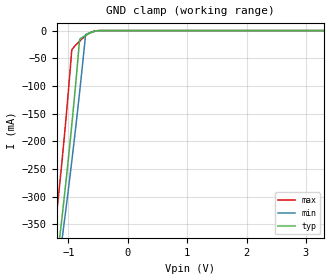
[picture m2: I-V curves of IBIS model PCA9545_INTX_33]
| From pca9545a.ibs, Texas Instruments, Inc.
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[Model]   PCA9545_INTX_33
Model_type  Input
Vinl=0.9
Vinh=2.52
| variable   typ   min   max
C_comp   2.06pF   1.51pF   4.70pF
[Temperature Range]   40   100   -40
| Ambient temperature   25   85   -40
[Voltage range]   3.3   3   3.6
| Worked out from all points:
|   GND clamp passes 1 mA (typ) near -0.54 V on its own axis
[GND Clamp]
| PCA9545_INTX_33
|   Voltage   I(typ)   I(min)   I(max)
-5.5V     -1.952A    -1.991A    -1.822A
-1.24V    -456.1mA   -482.2mA   -371.1mA
-1.205V   -425.8mA   -455.2mA   -337.1mA
-1.135V   -362.9mA   -399.8mA   -265.2mA
-1.1V     -330.1mA   -371.2mA   -227.1mA
-1.07V    -301.2mA   -346.3mA   -193.2mA
-1.005V   -236.2mA   -290.9mA   -115.2mA
-945mV    -172.6mA   -237.7mA   -36.94mA
-810mV    -16.02mA   -110.1mA   -19.15mA
-710mV    -8.623mA   -7.36mA    -9.218mA
-505mV    -240uA     -374.5uA   -17.49uA
3.3V      82.96pA    248pA      52.06pA
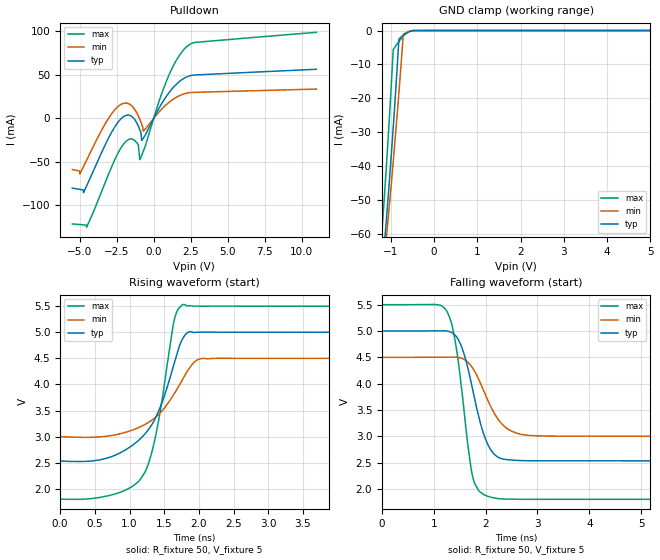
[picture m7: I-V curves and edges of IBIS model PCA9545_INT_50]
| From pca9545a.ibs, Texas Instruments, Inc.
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[Model]   PCA9545_INT_50
Model_type  Open_drain
Enable   Active-Low
Vref =   5V
Rref =   1k
Cref =   50p
Vmeas =   2.5
| variable   typ   min   max
C_comp   0.16pF   0.14pF   0.20pF
| C_pulldown   0.50pF   0.33pF   0.70pF
| C_tri-state   0.16pF   0.14pF   0.20pF
[Temperature Range]   40   100   -40
| Ambient temperature   25   85   -40
[Voltage range]   5   4.5   5.5
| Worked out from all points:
|   slope of the pulldown table from 0 to 0.75 V, typ, clamps not added: 33.3 ohm
|   GND clamp passes 1 mA (typ) near -0.66 V on its own axis
|   rising waveform, R_fixture 50, V_fixture 5: 20-80 % time 462ps typ, 504ps min, 300ps max; typ from 2.53 V to 5 V
|   falling waveform, R_fixture 50, V_fixture 5: 20-80 % time 368ps typ, 451ps min, 277ps max; typ from 5 V to 2.53 V
[GND Clamp]
| PCA9545_INT_50
|   Voltage   I(typ)   I(min)   I(max)
-5.5V     -353mA     -340.2mA   -363.4mA
-1.2V     -71.19mA   -74.19mA   -58.77mA
-1.125V   -59.7mA    -64.38mA   -44.86mA
-1.105V   -56.52mA   -61.69mA   -40.97mA
-1.09V    -54.11mA   -59.66mA   -37.99mA
-1.07V    -50.85mA   -56.93mA   -33.93mA
-940mV    -28.2mA    -38.37mA   -5.645mA
-810mV    -2.594mA   -18.16mA   -3.228mA
-710mV    -1.419mA   -1.185mA   -1.625mA
-620mV    -644.8uA   -525uA     -621.6uA
-480mV    -17.76uA   -26.37uA   -2.003uA
5V        25.68pA    51.58pA    20.07pA
[Pulldown]
| PCA9545_INT_50
|   Voltage   I(typ)   I(min)   I(max)
-5.5V     -80.34mA   -58.86mA   -121.5mA
-4.995V   -81.71mA   -64.14mA   -122.2mA
-4.54V    -77.91mA   -48.31mA   -125.2mA
-2.93V    -18.73mA   3.071mA    -59.3mA
-1.88V    3.271mA    17.54mA    -26.68mA
-1.1V     -6.735mA   4.862mA    -28.99mA
-940mV    -13.05mA   -1.186mA   -47.44mA
-810mV    -25.48mA   -6.932mA   -42.45mA
-705mV    -22.99mA   -14.69mA   -38.17mA
955mV     27.58mA    17.21mA    46.56mA
2.305V    48.12mA    29.18mA    83.35mA
11V       56.37mA    33.62mA    98.88mA
[Ramp]
| PCA9545_INT_50
| variable   typ   min   max
dV/dt_r   1.49/4.70E-10   0.91/5.19E-10   2.22/3.04E-10
dV/dt_f   1.48/3.76E-10   0.90/4.58E-10   2.22/2.81E-10
R_load = 50
[Rising Waveform]
| PCA9545_INT_50
R_fixture =   50
C_fixture =   0
L_fixture =   0
V_fixture =   5
V_fixture_min = 4.5
V_fixture_max = 5.5
|   Time   V(typ)   V(min)   V(max)
0s        2.534V     3.001V     1.803V
685ps     2.593V     3.011V     1.866V
1.19ns    3.005V     3.211V     2.249V
1.285ns   3.158V     3.283V     2.534V
1.385ns   3.387V     3.382V     3.069V
1.64ns    4.384V     3.812V     5.203V
1.78ns    4.907V     4.129V     5.53V
1.975ns   4.999V     4.467V     5.5V
2.285ns   5V         4.501V     5.5V
70ns      5V         4.5V       5.5V
[Falling Waveform]
| PCA9545_INT_50
R_fixture =   50
C_fixture =   0
L_fixture =   0
V_fixture =   5
V_fixture_min = 4.5
V_fixture_max = 5.5
|   Time   V(typ)   V(min)   V(max)
0s        5V         4.5V       5.5V
1.235ns   5.002V     4.503V     5.401V
1.335ns   4.976V     4.504V     5.166V
1.425ns   4.904V     4.504V     4.726V
1.675ns   4.22V      4.39V      2.697V
1.77ns    3.793V     4.262V     2.157V
2.03ns    2.87V      3.709V     1.866V
2.335ns   2.569V     3.212V     1.81V
3.535ns   2.534V     3.003V     1.803V
70ns      2.534V     3.001V     1.803V
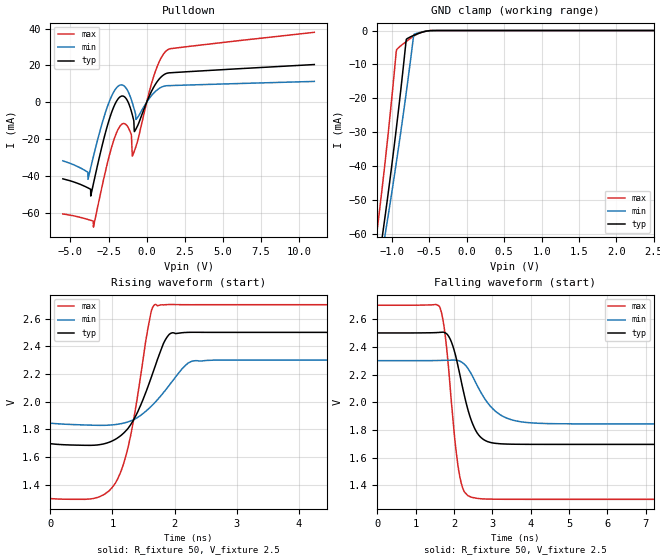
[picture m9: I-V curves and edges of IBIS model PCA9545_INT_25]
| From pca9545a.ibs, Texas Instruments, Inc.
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[Model]   PCA9545_INT_25
Model_type  Open_drain
Enable   Active-Low
Vref =   2.5V
Rref =   1k
Cref =   50p
Vmeas =   1.25
| variable   typ   min   max
C_comp   0.17pF   0.15pF   0.20pF
| C_pulldown   0.56pF   0.33pF   0.80pF
| C_tri-state   0.17pF   0.15pF   0.20pF
[Temperature Range]   40   100   -40
| Ambient temperature   25   85   -40
[Voltage range]   2.5   2.3   2.7
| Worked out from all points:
|   slope of the pulldown table from 0 to 0.375 V, typ, clamps not added: 54.5 ohm
|   GND clamp passes 1 mA (typ) near -0.66 V on its own axis
|   rising waveform, R_fixture 50, V_fixture 2.5: 20-80 % time 427ps typ, 521ps min, 331ps max; typ from 1.7 V to 2.5 V
|   falling waveform, R_fixture 50, V_fixture 2.5: 20-80 % time 429ps typ, 640ps min, 289ps max; typ from 2.5 V to 1.7 V
[GND Clamp]
| PCA9545_INT_25
|   Voltage   I(typ)   I(min)   I(max)
-5.5V     -353mA     -340.2mA   -363.4mA
-1.2V     -71.19mA   -74.19mA   -58.77mA
-1.125V   -59.7mA    -64.38mA   -44.86mA
-1.105V   -56.52mA   -61.69mA   -40.97mA
-1.09V    -54.11mA   -59.66mA   -37.99mA
-1.07V    -50.85mA   -56.93mA   -33.93mA
-945mV    -29.12mA   -39.11mA   -6.244mA
-940mV    -28.2mA    -38.37mA   -5.645mA
-810mV    -2.594mA   -18.16mA   -3.228mA
-710mV    -1.419mA   -1.185mA   -1.625mA
-485mV    -24.54uA   -33.77uA   -3.202uA
2.5V      13.93pA    36.49pA    10.03pA
[Pulldown]
| PCA9545_INT_25
|   Voltage   I(typ)   I(min)   I(max)
-5.5V     -41.57mA   -31.81mA   -60.64mA
-3.85V    -46.5mA    -41.81mA   -63.65mA
-3.495V   -44.26mA   -29.46mA   -67.82mA
-1.925V   1.268mA    8.331mA    -15.55mA
-1.235V   395.9uA    6.092mA    -13.4mA
-1.005V   -4.915mA   1.381mA    -17.58mA
-935mV    -7.028mA   -434uA     -29.18mA
-800mV    -15.85mA   -4.299mA   -26.3mA
-700mV    -14.46mA   -9.307mA   -23.95mA
480mV     8.469mA    5.142mA    14.54mA
1.35V     15.81mA    9.004mA    28.36mA
11V       20.49mA    11.32mA    37.98mA
[Ramp]
| PCA9545_INT_25
| variable   typ   min   max
dV/dt_r   0.49/4.42E-10   0.28/5.49E-10   0.84/3.38E-10
dV/dt_f   0.49/4.38E-10   0.28/6.48E-10   0.84/2.97E-10
R_load = 50
[Rising Waveform]
| PCA9545_INT_25
R_fixture =   50
C_fixture =   0
L_fixture =   0
V_fixture =   2.5
V_fixture_min = 2.3
V_fixture_max = 2.7
|   Time   V(typ)   V(min)   V(max)
0s        1.695V     1.843V     1.299V
740ps     1.685V     1.828V     1.304V
1.065ns   1.732V     1.835V     1.425V
1.27ns    1.818V     1.856V     1.706V
1.59ns    2.131V     1.951V     2.575V
1.69ns    2.259V     1.996V     2.702V
1.94ns    2.494V     2.133V     2.701V
2.25ns    2.501V     2.286V     2.7V
2.725ns   2.5V       2.3V       2.7V
70ns      2.5V       2.3V       2.7V
[Falling Waveform]
| PCA9545_INT_25
R_fixture =   50
C_fixture =   0
L_fixture =   0
V_fixture =   2.5
V_fixture_min = 2.3
V_fixture_max = 2.7
|   Time   V(typ)   V(min)   V(max)
0s        2.5V       2.3V       2.7V
1.625ns   2.504V     2.301V     2.691V
1.775ns   2.5V       2.303V     2.48V
2.025ns   2.357V     2.304V     1.73V
2.17ns    2.181V     2.295V     1.442V
2.44ns    1.88V      2.211V     1.316V
2.715ns   1.743V     2.066V     1.303V
3.385ns   1.698V     1.884V     1.299V
4.705ns   1.695V     1.845V     1.299V
70ns      1.695V     1.843V     1.299V
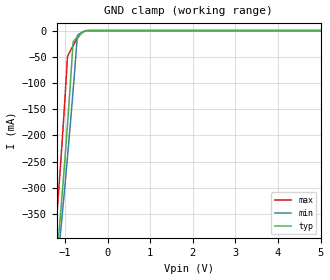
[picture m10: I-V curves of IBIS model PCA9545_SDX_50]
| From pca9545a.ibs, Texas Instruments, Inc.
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[Model]   PCA9545_SDX_50
Model_type  Terminator
| variable   typ   min   max
C_comp   3.78pF   2.70pF   7.90pF
| C_tri-state   3.78pF   2.70pF   7.90pF
[Temperature Range]   40   100   -40
| Ambient temperature   25   85   -40
[Voltage range]   5   4.5   5.5
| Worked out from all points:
|   GND clamp passes 1 mA (typ) near -0.53 V on its own axis
[GND Clamp]
| PCA9545_SDX_50
|   Voltage   I(typ)   I(min)   I(max)
-5.5V     -2.377A    -2.363A    -2.337A
-1.24V    -474.4mA   -493.9mA   -400.8mA
-1.205V   -442.9mA   -466.2mA   -364.9mA
-1.145V   -387.2mA   -417.4mA   -300.6mA
-1.115V   -358.5mA   -392.5mA   -266.9mA
-1.085V   -329.1mA   -367.2mA   -232.1mA
-1.025V   -268.1mA   -315.3mA   -158.8mA
-945mV    -181.8mA   -243.4mA   -52.16mA
-810mV    -21.83mA   -113.4mA   -28.62mA
-710mV    -12.16mA   -9.38mA    -14.54mA
-560mV    -2.215mA   -1.917mA   -1.504mA
5V        171.3pA    446.4pA    114.6pA
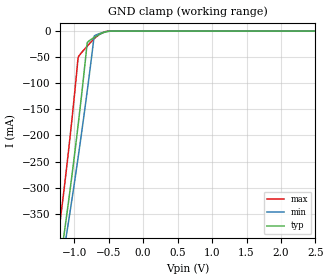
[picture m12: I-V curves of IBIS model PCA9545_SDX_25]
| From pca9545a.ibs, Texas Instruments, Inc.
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[Model]   PCA9545_SDX_25
Model_type  Terminator
| variable   typ   min   max
C_comp   2.83pF   2.22pF   3.63pF
| C_tri-state   2.83pF   2.22pF   3.63pF
[Temperature Range]   40   100   -40
| Ambient temperature   25   85   -40
[Voltage range]   2.5   2.3   2.7
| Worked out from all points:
|   GND clamp passes 1 mA (typ) near -0.53 V on its own axis
[GND Clamp]
| PCA9545_SDX_25
|   Voltage   I(typ)   I(min)   I(max)
-5.5V     -2.377A    -2.363A    -2.337A
-1.24V    -474.4mA   -493.9mA   -400.8mA
-1.205V   -442.9mA   -466.2mA   -364.9mA
-1.145V   -387.2mA   -417.4mA   -300.6mA
-1.115V   -358.5mA   -392.5mA   -266.9mA
-1.085V   -329.1mA   -367.2mA   -232.1mA
-1.025V   -268.1mA   -315.3mA   -158.8mA
-945mV    -181.8mA   -243.4mA   -52.16mA
-810mV    -21.83mA   -113.4mA   -28.62mA
-710mV    -12.16mA   -9.38mA    -14.54mA
-490mV    -198uA     -284.5uA   -29.52uA
2.5V      93.62pA    331.8pA    56.87pA
